VERSION 5.8 ;
BUSBITCHARS "[]" ;
DIVIDERCHAR "/" ;
UNITS
    DATABASE MICRONS 1000 ;
END UNITS

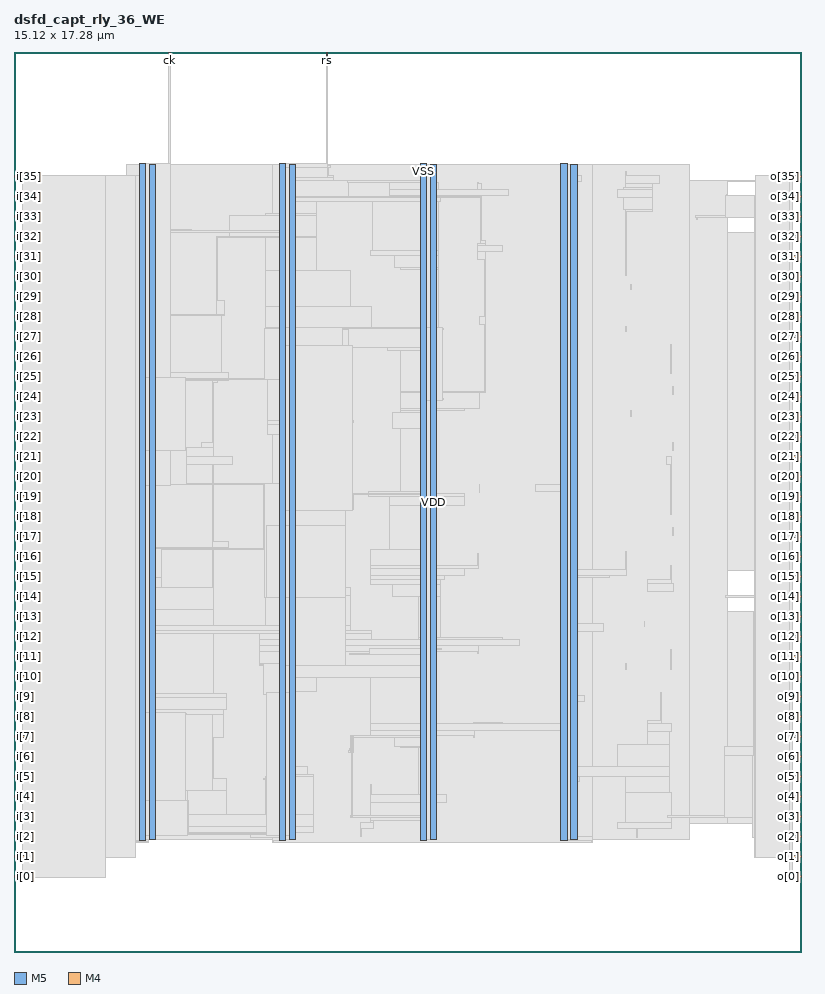
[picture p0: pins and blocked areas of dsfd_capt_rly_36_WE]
MACRO dsfd_capt_rly_36_WE
  FOREIGN dsfd_capt_rly_36_WE 0 0 ;
  CLASS BLOCK ;
  SIZE 15.12 BY 17.28 ;
  PIN ck
    DIRECTION INPUT ;
    USE SIGNAL ;
    PORT
      LAYER M5 ;
        RECT  2.976 17.088 3 17.28 ;
    END
  END ck
  PIN i[0]
    DIRECTION INPUT ;
    USE SIGNAL ;
    PORT
      LAYER M4 ;
        RECT  0 1.44 0.192 1.464 ;
    END
  END i[0]
  PIN i[10]
    DIRECTION INPUT ;
    USE SIGNAL ;
    PORT
      LAYER M4 ;
        RECT  0 5.28 0.192 5.304 ;
    END
  END i[10]
  PIN i[11]
    DIRECTION INPUT ;
    USE SIGNAL ;
    PORT
      LAYER M4 ;
        RECT  0 5.664 0.192 5.688 ;
    END
  END i[11]
  PIN i[12]
    DIRECTION INPUT ;
    USE SIGNAL ;
    PORT
      LAYER M4 ;
        RECT  0 6.048 0.192 6.072 ;
    END
  END i[12]
  PIN i[13]
    DIRECTION INPUT ;
    USE SIGNAL ;
    PORT
      LAYER M4 ;
        RECT  0 6.432 0.192 6.456 ;
    END
  END i[13]
  PIN i[14]
    DIRECTION INPUT ;
    USE SIGNAL ;
    PORT
      LAYER M4 ;
        RECT  0 6.816 0.192 6.84 ;
    END
  END i[14]
  PIN i[15]
    DIRECTION INPUT ;
    USE SIGNAL ;
    PORT
      LAYER M4 ;
        RECT  0 7.2 0.192 7.224 ;
    END
  END i[15]
  PIN i[16]
    DIRECTION INPUT ;
    USE SIGNAL ;
    PORT
      LAYER M4 ;
        RECT  0 7.584 0.192 7.608 ;
    END
  END i[16]
  PIN i[17]
    DIRECTION INPUT ;
    USE SIGNAL ;
    PORT
      LAYER M4 ;
        RECT  0 7.968 0.192 7.992 ;
    END
  END i[17]
  PIN i[18]
    DIRECTION INPUT ;
    USE SIGNAL ;
    PORT
      LAYER M4 ;
        RECT  0 8.352 0.192 8.376 ;
    END
  END i[18]
  PIN i[19]
    DIRECTION INPUT ;
    USE SIGNAL ;
    PORT
      LAYER M4 ;
        RECT  0 8.736 0.192 8.76 ;
    END
  END i[19]
  PIN i[1]
    DIRECTION INPUT ;
    USE SIGNAL ;
    PORT
      LAYER M4 ;
        RECT  0 1.824 0.192 1.848 ;
    END
  END i[1]
  PIN i[20]
    DIRECTION INPUT ;
    USE SIGNAL ;
    PORT
      LAYER M4 ;
        RECT  0 9.12 0.192 9.144 ;
    END
  END i[20]
  PIN i[21]
    DIRECTION INPUT ;
    USE SIGNAL ;
    PORT
      LAYER M4 ;
        RECT  0 9.504 0.192 9.528 ;
    END
  END i[21]
  PIN i[22]
    DIRECTION INPUT ;
    USE SIGNAL ;
    PORT
      LAYER M4 ;
        RECT  0 9.888 0.192 9.912 ;
    END
  END i[22]
  PIN i[23]
    DIRECTION INPUT ;
    USE SIGNAL ;
    PORT
      LAYER M4 ;
        RECT  0 10.272 0.192 10.296 ;
    END
  END i[23]
  PIN i[24]
    DIRECTION INPUT ;
    USE SIGNAL ;
    PORT
      LAYER M4 ;
        RECT  0 10.656 0.192 10.68 ;
    END
  END i[24]
  PIN i[25]
    DIRECTION INPUT ;
    USE SIGNAL ;
    PORT
      LAYER M4 ;
        RECT  0 11.04 0.192 11.064 ;
    END
  END i[25]
  PIN i[26]
    DIRECTION INPUT ;
    USE SIGNAL ;
    PORT
      LAYER M4 ;
        RECT  0 11.424 0.192 11.448 ;
    END
  END i[26]
  PIN i[27]
    DIRECTION INPUT ;
    USE SIGNAL ;
    PORT
      LAYER M4 ;
        RECT  0 11.808 0.192 11.832 ;
    END
  END i[27]
  PIN i[28]
    DIRECTION INPUT ;
    USE SIGNAL ;
    PORT
      LAYER M4 ;
        RECT  0 12.192 0.192 12.216 ;
    END
  END i[28]
  PIN i[29]
    DIRECTION INPUT ;
    USE SIGNAL ;
    PORT
      LAYER M4 ;
        RECT  0 12.576 0.192 12.6 ;
    END
  END i[29]
  PIN i[2]
    DIRECTION INPUT ;
    USE SIGNAL ;
    PORT
      LAYER M4 ;
        RECT  0 2.208 0.192 2.232 ;
    END
  END i[2]
  PIN i[30]
    DIRECTION INPUT ;
    USE SIGNAL ;
    PORT
      LAYER M4 ;
        RECT  0 12.96 0.192 12.984 ;
    END
  END i[30]
  PIN i[31]
    DIRECTION INPUT ;
    USE SIGNAL ;
    PORT
      LAYER M4 ;
        RECT  0 13.344 0.192 13.368 ;
    END
  END i[31]
  PIN i[32]
    DIRECTION INPUT ;
    USE SIGNAL ;
    PORT
      LAYER M4 ;
        RECT  0 13.728 0.192 13.752 ;
    END
  END i[32]
  PIN i[33]
    DIRECTION INPUT ;
    USE SIGNAL ;
    PORT
      LAYER M4 ;
        RECT  0 14.112 0.192 14.136 ;
    END
  END i[33]
  PIN i[34]
    DIRECTION INPUT ;
    USE SIGNAL ;
    PORT
      LAYER M4 ;
        RECT  0 14.496 0.192 14.52 ;
    END
  END i[34]
  PIN i[35]
    DIRECTION INPUT ;
    USE SIGNAL ;
    PORT
      LAYER M4 ;
        RECT  0 14.88 0.192 14.904 ;
    END
  END i[35]
  PIN i[3]
    DIRECTION INPUT ;
    USE SIGNAL ;
    PORT
      LAYER M4 ;
        RECT  0 2.592 0.192 2.616 ;
    END
  END i[3]
  PIN i[4]
    DIRECTION INPUT ;
    USE SIGNAL ;
    PORT
      LAYER M4 ;
        RECT  0 2.976 0.192 3 ;
    END
  END i[4]
  PIN i[5]
    DIRECTION INPUT ;
    USE SIGNAL ;
    PORT
      LAYER M4 ;
        RECT  0 3.36 0.192 3.384 ;
    END
  END i[5]
  PIN i[6]
    DIRECTION INPUT ;
    USE SIGNAL ;
    PORT
      LAYER M4 ;
        RECT  0 3.744 0.192 3.768 ;
    END
  END i[6]
  PIN i[7]
    DIRECTION INPUT ;
    USE SIGNAL ;
    PORT
      LAYER M4 ;
        RECT  0 4.128 0.192 4.152 ;
    END
  END i[7]
  PIN i[8]
    DIRECTION INPUT ;
    USE SIGNAL ;
    PORT
      LAYER M4 ;
        RECT  0 4.512 0.192 4.536 ;
    END
  END i[8]
  PIN i[9]
    DIRECTION INPUT ;
    USE SIGNAL ;
    PORT
      LAYER M4 ;
        RECT  0 4.896 0.192 4.92 ;
    END
  END i[9]
  PIN o[0]
    DIRECTION OUTPUT ;
    USE SIGNAL ;
    PORT
      LAYER M4 ;
        RECT  14.928 1.44 15.12 1.464 ;
    END
  END o[0]
  PIN o[10]
    DIRECTION OUTPUT ;
    USE SIGNAL ;
    PORT
      LAYER M4 ;
        RECT  14.928 5.28 15.12 5.304 ;
    END
  END o[10]
  PIN o[11]
    DIRECTION OUTPUT ;
    USE SIGNAL ;
    PORT
      LAYER M4 ;
        RECT  14.928 5.664 15.12 5.688 ;
    END
  END o[11]
  PIN o[12]
    DIRECTION OUTPUT ;
    USE SIGNAL ;
    PORT
      LAYER M4 ;
        RECT  14.928 6.048 15.12 6.072 ;
    END
  END o[12]
  PIN o[13]
    DIRECTION OUTPUT ;
    USE SIGNAL ;
    PORT
      LAYER M4 ;
        RECT  14.928 6.432 15.12 6.456 ;
    END
  END o[13]
  PIN o[14]
    DIRECTION OUTPUT ;
    USE SIGNAL ;
    PORT
      LAYER M4 ;
        RECT  14.928 6.816 15.12 6.84 ;
    END
  END o[14]
  PIN o[15]
    DIRECTION OUTPUT ;
    USE SIGNAL ;
    PORT
      LAYER M4 ;
        RECT  14.928 7.2 15.12 7.224 ;
    END
  END o[15]
  PIN o[16]
    DIRECTION OUTPUT ;
    USE SIGNAL ;
    PORT
      LAYER M4 ;
        RECT  14.928 7.584 15.12 7.608 ;
    END
  END o[16]
  PIN o[17]
    DIRECTION OUTPUT ;
    USE SIGNAL ;
    PORT
      LAYER M4 ;
        RECT  14.928 7.968 15.12 7.992 ;
    END
  END o[17]
  PIN o[18]
    DIRECTION OUTPUT ;
    USE SIGNAL ;
    PORT
      LAYER M4 ;
        RECT  14.928 8.352 15.12 8.376 ;
    END
  END o[18]
  PIN o[19]
    DIRECTION OUTPUT ;
    USE SIGNAL ;
    PORT
      LAYER M4 ;
        RECT  14.928 8.736 15.12 8.76 ;
    END
  END o[19]
  PIN o[1]
    DIRECTION OUTPUT ;
    USE SIGNAL ;
    PORT
      LAYER M4 ;
        RECT  14.928 1.824 15.12 1.848 ;
    END
  END o[1]
  PIN o[20]
    DIRECTION OUTPUT ;
    USE SIGNAL ;
    PORT
      LAYER M4 ;
        RECT  14.928 9.12 15.12 9.144 ;
    END
  END o[20]
  PIN o[21]
    DIRECTION OUTPUT ;
    USE SIGNAL ;
    PORT
      LAYER M4 ;
        RECT  14.928 9.504 15.12 9.528 ;
    END
  END o[21]
  PIN o[22]
    DIRECTION OUTPUT ;
    USE SIGNAL ;
    PORT
      LAYER M4 ;
        RECT  14.928 9.888 15.12 9.912 ;
    END
  END o[22]
  PIN o[23]
    DIRECTION OUTPUT ;
    USE SIGNAL ;
    PORT
      LAYER M4 ;
        RECT  14.928 10.272 15.12 10.296 ;
    END
  END o[23]
  PIN o[24]
    DIRECTION OUTPUT ;
    USE SIGNAL ;
    PORT
      LAYER M4 ;
        RECT  14.928 10.656 15.12 10.68 ;
    END
  END o[24]
  PIN o[25]
    DIRECTION OUTPUT ;
    USE SIGNAL ;
    PORT
      LAYER M4 ;
        RECT  14.928 11.04 15.12 11.064 ;
    END
  END o[25]
  PIN o[26]
    DIRECTION OUTPUT ;
    USE SIGNAL ;
    PORT
      LAYER M4 ;
        RECT  14.928 11.424 15.12 11.448 ;
    END
  END o[26]
  PIN o[27]
    DIRECTION OUTPUT ;
    USE SIGNAL ;
    PORT
      LAYER M4 ;
        RECT  14.928 11.808 15.12 11.832 ;
    END
  END o[27]
  PIN o[28]
    DIRECTION OUTPUT ;
    USE SIGNAL ;
    PORT
      LAYER M4 ;
        RECT  14.928 12.192 15.12 12.216 ;
    END
  END o[28]
  PIN o[29]
    DIRECTION OUTPUT ;
    USE SIGNAL ;
    PORT
      LAYER M4 ;
        RECT  14.928 12.576 15.12 12.6 ;
    END
  END o[29]
  PIN o[2]
    DIRECTION OUTPUT ;
    USE SIGNAL ;
    PORT
      LAYER M4 ;
        RECT  14.928 2.208 15.12 2.232 ;
    END
  END o[2]
  PIN o[30]
    DIRECTION OUTPUT ;
    USE SIGNAL ;
    PORT
      LAYER M4 ;
        RECT  14.928 12.96 15.12 12.984 ;
    END
  END o[30]
  PIN o[31]
    DIRECTION OUTPUT ;
    USE SIGNAL ;
    PORT
      LAYER M4 ;
        RECT  14.928 13.344 15.12 13.368 ;
    END
  END o[31]
  PIN o[32]
    DIRECTION OUTPUT ;
    USE SIGNAL ;
    PORT
      LAYER M4 ;
        RECT  14.928 13.728 15.12 13.752 ;
    END
  END o[32]
  PIN o[33]
    DIRECTION OUTPUT ;
    USE SIGNAL ;
    PORT
      LAYER M4 ;
        RECT  14.928 14.112 15.12 14.136 ;
    END
  END o[33]
  PIN o[34]
    DIRECTION OUTPUT ;
    USE SIGNAL ;
    PORT
      LAYER M4 ;
        RECT  14.928 14.496 15.12 14.52 ;
    END
  END o[34]
  PIN o[35]
    DIRECTION OUTPUT ;
    USE SIGNAL ;
    PORT
      LAYER M4 ;
        RECT  14.928 14.88 15.12 14.904 ;
    END
  END o[35]
  PIN o[3]
    DIRECTION OUTPUT ;
    USE SIGNAL ;
    PORT
      LAYER M4 ;
        RECT  14.928 2.592 15.12 2.616 ;
    END
  END o[3]
  PIN o[4]
    DIRECTION OUTPUT ;
    USE SIGNAL ;
    PORT
      LAYER M4 ;
        RECT  14.928 2.976 15.12 3 ;
    END
  END o[4]
  PIN o[5]
    DIRECTION OUTPUT ;
    USE SIGNAL ;
    PORT
      LAYER M4 ;
        RECT  14.928 3.36 15.12 3.384 ;
    END
  END o[5]
  PIN o[6]
    DIRECTION OUTPUT ;
    USE SIGNAL ;
    PORT
      LAYER M4 ;
        RECT  14.928 3.744 15.12 3.768 ;
    END
  END o[6]
  PIN o[7]
    DIRECTION OUTPUT ;
    USE SIGNAL ;
    PORT
      LAYER M4 ;
        RECT  14.928 4.128 15.12 4.152 ;
    END
  END o[7]
  PIN o[8]
    DIRECTION OUTPUT ;
    USE SIGNAL ;
    PORT
      LAYER M4 ;
        RECT  14.928 4.512 15.12 4.536 ;
    END
  END o[8]
  PIN o[9]
    DIRECTION OUTPUT ;
    USE SIGNAL ;
    PORT
      LAYER M4 ;
        RECT  14.928 4.896 15.12 4.92 ;
    END
  END o[9]
  PIN rs
    DIRECTION INPUT ;
    USE SIGNAL ;
    PORT
      LAYER M5 ;
        RECT  6 17.088 6.024 17.28 ;
    END
  END rs
  PIN VDD
    DIRECTION INOUT ;
    USE POWER ;
    PORT
      LAYER M5 ;
        RECT  10.692 2.151 10.812 15.129 ;
        RECT  7.992 2.151 8.112 15.129 ;
        RECT  5.292 2.151 5.412 15.129 ;
        RECT  2.592 2.151 2.712 15.129 ;
    END
  END VDD
  PIN VSS
    DIRECTION INOUT ;
    USE GROUND ;
    PORT
      LAYER M5 ;
        RECT  10.5 2.137 10.62 15.143 ;
        RECT  7.8 2.137 7.92 15.143 ;
        RECT  5.1 2.137 5.22 15.143 ;
        RECT  2.4 2.137 2.52 15.143 ;
    END
  END VSS
  OBS
    LAYER RVTN ;
     RECT  2.16 2.16 12.96 2.295 ;
     RECT  2.16 2.565 12.96 2.835 ;
     RECT  2.16 3.105 12.96 3.375 ;
     RECT  2.16 3.645 12.96 3.915 ;
     RECT  2.16 4.185 12.96 4.455 ;
     RECT  2.16 4.725 12.96 4.995 ;
     RECT  2.16 5.265 12.96 5.535 ;
     RECT  2.16 5.805 12.96 6.075 ;
     RECT  2.16 6.345 12.96 6.615 ;
     RECT  2.16 6.885 12.96 7.155 ;
     RECT  2.16 7.425 12.96 7.695 ;
     RECT  2.16 7.965 12.96 8.235 ;
     RECT  2.16 8.505 12.96 8.775 ;
     RECT  2.16 9.045 12.96 9.315 ;
     RECT  2.16 9.585 12.96 9.855 ;
     RECT  2.16 10.125 12.96 10.395 ;
     RECT  2.16 10.665 12.96 10.935 ;
     RECT  2.16 11.205 12.96 11.475 ;
     RECT  2.16 11.745 12.96 12.015 ;
     RECT  2.16 12.285 12.96 12.555 ;
     RECT  2.16 12.825 12.96 13.095 ;
     RECT  2.16 13.365 12.96 13.635 ;
     RECT  2.16 13.905 12.96 14.175 ;
     RECT  2.16 14.445 12.96 14.715 ;
     RECT  2.16 14.985 12.96 15.12 ;
    LAYER RVTP ;
     RECT  2.16 2.295 12.96 2.565 ;
     RECT  2.16 2.835 12.96 3.105 ;
     RECT  2.16 3.375 12.96 3.645 ;
     RECT  2.16 3.915 12.96 4.185 ;
     RECT  2.16 4.455 12.96 4.725 ;
     RECT  2.16 4.995 12.96 5.265 ;
     RECT  2.16 5.535 12.96 5.805 ;
     RECT  2.16 6.075 12.96 6.345 ;
     RECT  2.16 6.615 12.96 6.885 ;
     RECT  2.16 7.155 12.96 7.425 ;
     RECT  2.16 7.695 12.96 7.965 ;
     RECT  2.16 8.235 12.96 8.505 ;
     RECT  2.16 8.775 12.96 9.045 ;
     RECT  2.16 9.315 12.96 9.585 ;
     RECT  2.16 9.855 12.96 10.125 ;
     RECT  2.16 10.395 12.96 10.665 ;
     RECT  2.16 10.935 12.96 11.205 ;
     RECT  2.16 11.475 12.96 11.745 ;
     RECT  2.16 12.015 12.96 12.285 ;
     RECT  2.16 12.555 12.96 12.825 ;
     RECT  2.16 13.095 12.96 13.365 ;
     RECT  2.16 13.635 12.96 13.905 ;
     RECT  2.16 14.175 12.96 14.445 ;
     RECT  2.16 14.715 12.96 14.985 ;
    LAYER M1 ;
     RECT  2.16 2.151 12.96 15.129 ;
    LAYER M2 ;
     RECT  1.723 2.106 2.16 2.124 ;
     RECT  2.16 2.106 2.579 15.129 ;
     RECT  2.579 2.151 4.963 15.129 ;
     RECT  4.963 2.106 11.111 15.129 ;
     RECT  11.111 2.151 12.96 15.129 ;
     RECT  12.96 2.466 13.703 14.814 ;
     RECT  13.703 2.466 14.207 6.534 ;
     RECT  14.207 3.006 14.243 3.294 ;
     RECT  14.207 4.122 14.243 6.534 ;
     RECT  13.703 7.326 14.243 13.824 ;
     RECT  13.703 14.796 14.279 14.814 ;
     RECT  14.243 3.006 14.927 3.024 ;
     RECT  14.243 7.938 14.927 7.956 ;
     RECT  14.243 11.376 14.927 11.394 ;
    LAYER M3 ;
     RECT  1.728 1.435 1.746 1.819 ;
     RECT  14.904 1.435 14.922 1.819 ;
     RECT  1.728 1.819 2.322 2.101 ;
     RECT  1.728 2.101 2.574 2.129 ;
     RECT  4.968 2.101 4.986 2.143 ;
     RECT  11.088 2.101 11.106 2.143 ;
     RECT  4.968 2.143 5.205 2.191 ;
     RECT  14.22 1.819 14.922 2.203 ;
     RECT  10.515 2.143 11.106 2.219 ;
     RECT  2.268 2.129 2.574 2.255 ;
     RECT  3.312 2.251 3.33 2.299 ;
     RECT  4.536 2.191 5.205 2.299 ;
     RECT  6.66 2.227 6.678 2.371 ;
     RECT  11.952 2.191 11.97 2.371 ;
     RECT  2.304 2.255 2.574 2.413 ;
     RECT  3.312 2.299 5.742 2.413 ;
     RECT  7.815 2.143 7.905 2.413 ;
     RECT  6.66 2.371 6.894 2.489 ;
     RECT  11.592 2.371 12.618 2.489 ;
     RECT  6.84 2.489 6.894 2.533 ;
     RECT  7.815 2.413 8.097 2.533 ;
     RECT  2.304 2.413 5.742 2.633 ;
     RECT  6.84 2.533 8.097 2.875 ;
     RECT  6.84 2.875 8.298 3.029 ;
     RECT  14.184 2.203 14.922 3.029 ;
     RECT  11.736 2.489 12.618 3.065 ;
     RECT  2.304 2.633 4.086 3.101 ;
     RECT  6.84 3.029 6.858 3.209 ;
     RECT  10.515 2.219 10.797 3.271 ;
     RECT  14.184 3.029 14.238 3.299 ;
     RECT  3.816 3.101 4.086 3.335 ;
     RECT  14.184 3.299 14.202 3.355 ;
     RECT  4.824 2.633 5.742 3.371 ;
     RECT  10.515 3.271 10.854 3.379 ;
     RECT  11.736 3.065 12.582 3.379 ;
     RECT  2.304 3.101 2.826 3.389 ;
     RECT  5.115 3.371 5.742 3.407 ;
     RECT  5.115 3.407 5.634 3.569 ;
     RECT  10.515 3.379 12.582 3.569 ;
     RECT  2.304 3.389 2.697 3.875 ;
     RECT  6.444 3.835 6.462 3.911 ;
     RECT  7.776 3.029 8.097 3.919 ;
     RECT  13.644 3.355 14.202 3.947 ;
     RECT  7.416 3.919 8.097 3.955 ;
     RECT  11.592 3.569 12.582 3.983 ;
     RECT  2.415 3.875 2.697 4.117 ;
     RECT  3.816 3.335 3.834 4.117 ;
     RECT  7.308 3.955 8.097 4.117 ;
     RECT  6.84 4.117 8.097 4.153 ;
     RECT  8.82 4.117 8.838 4.153 ;
     RECT  12.168 3.983 12.582 4.225 ;
     RECT  6.84 4.153 8.838 4.261 ;
     RECT  10.515 3.569 10.797 4.261 ;
     RECT  6.84 4.261 10.797 4.379 ;
     RECT  12.168 4.225 12.618 4.379 ;
     RECT  8.82 4.379 9.378 4.415 ;
     RECT  12.168 4.379 12.438 4.451 ;
     RECT  2.415 4.117 2.754 4.555 ;
     RECT  3.816 4.117 4.014 4.555 ;
     RECT  2.415 4.555 4.014 4.657 ;
     RECT  10.515 4.379 10.797 4.801 ;
     RECT  2.415 4.657 4.086 4.891 ;
     RECT  10.515 4.801 10.962 4.919 ;
     RECT  5.115 3.569 5.397 4.939 ;
     RECT  2.304 4.891 4.086 4.955 ;
     RECT  12.42 4.451 12.438 4.991 ;
     RECT  4.824 4.939 5.397 4.999 ;
     RECT  4.824 4.999 5.814 5.269 ;
     RECT  6.84 4.379 8.097 5.269 ;
     RECT  4.824 5.269 8.097 5.503 ;
     RECT  11.736 5.431 11.754 5.531 ;
     RECT  4.716 5.503 8.097 5.773 ;
     RECT  8.892 5.737 8.91 5.773 ;
     RECT  12.6 5.431 12.618 5.801 ;
     RECT  4.716 5.773 8.91 5.881 ;
     RECT  4.716 5.881 9.702 5.999 ;
     RECT  7.776 5.999 9.378 6.035 ;
     RECT  2.304 4.955 3.834 6.115 ;
     RECT  4.716 5.999 6.858 6.115 ;
     RECT  10.515 4.919 10.797 6.151 ;
     RECT  2.304 6.115 6.858 6.179 ;
     RECT  2.304 6.179 6.462 6.269 ;
     RECT  10.515 6.151 11.322 6.305 ;
     RECT  12.096 6.241 12.114 6.341 ;
     RECT  2.304 6.269 3.834 6.575 ;
     RECT  14.22 4.117 14.238 6.808 ;
     RECT  7.776 6.035 8.19 6.817 ;
     RECT  4.824 6.269 6.462 6.845 ;
     RECT  13.68 6.808 14.238 6.845 ;
     RECT  2.415 6.575 3.834 6.989 ;
     RECT  5.115 6.845 6.462 6.989 ;
     RECT  7.272 6.817 8.19 7.051 ;
     RECT  12.168 6.925 12.654 7.079 ;
     RECT  12.168 7.079 12.618 7.151 ;
     RECT  6.84 7.051 8.19 7.159 ;
     RECT  10.515 6.305 10.797 7.195 ;
     RECT  6.84 7.159 8.262 7.231 ;
     RECT  10.515 7.195 11.43 7.231 ;
     RECT  10.515 7.231 11.754 7.349 ;
     RECT  6.84 7.231 8.658 7.357 ;
     RECT  6.84 7.357 8.91 7.421 ;
     RECT  12.6 7.151 12.618 7.421 ;
     RECT  2.415 6.989 2.826 7.579 ;
     RECT  14.22 6.845 14.238 7.619 ;
     RECT  8.892 7.421 8.91 7.655 ;
     RECT  11.736 7.349 11.754 7.691 ;
     RECT  2.304 7.579 2.826 7.723 ;
     RECT  3.816 6.989 3.834 7.723 ;
     RECT  6.84 7.421 8.097 7.727 ;
     RECT  2.304 7.723 3.834 7.735 ;
     RECT  2.304 7.735 4.122 7.763 ;
     RECT  3.816 7.763 4.122 7.889 ;
     RECT  14.904 7.933 14.922 7.997 ;
     RECT  5.115 6.989 5.814 8.155 ;
     RECT  12.636 8.005 12.654 8.159 ;
     RECT  2.304 7.763 2.697 8.195 ;
     RECT  4.824 8.155 5.814 8.231 ;
     RECT  5.115 8.231 5.814 8.491 ;
     RECT  5.115 8.491 6.462 8.537 ;
     RECT  7.2 7.727 8.097 8.581 ;
     RECT  7.2 8.581 8.658 8.743 ;
     RECT  6.804 8.743 8.658 8.807 ;
     RECT  6.804 8.807 8.097 8.843 ;
     RECT  10.515 7.349 10.797 8.851 ;
     RECT  8.928 8.815 8.946 8.969 ;
     RECT  10.008 8.851 10.797 8.969 ;
     RECT  2.415 8.195 2.697 9.115 ;
     RECT  2.304 9.115 2.697 9.355 ;
     RECT  3.816 7.889 3.834 9.355 ;
     RECT  12.6 8.401 12.618 9.355 ;
     RECT  5.115 8.537 6.03 9.391 ;
     RECT  2.304 9.355 4.194 9.509 ;
     RECT  12.528 9.355 12.618 9.509 ;
     RECT  2.304 9.509 3.834 9.677 ;
     RECT  3.6 9.677 3.834 9.779 ;
     RECT  12.636 9.625 12.654 9.779 ;
     RECT  5.115 9.391 6.246 9.931 ;
     RECT  7.416 8.843 8.097 10.057 ;
     RECT  4.86 9.931 6.246 10.129 ;
     RECT  4.86 10.129 6.462 10.205 ;
     RECT  7.272 10.057 8.097 10.355 ;
     RECT  11.844 10.291 11.862 10.391 ;
     RECT  7.416 10.355 8.097 10.399 ;
     RECT  7.416 10.399 8.658 10.435 ;
     RECT  2.304 9.677 2.697 10.741 ;
     RECT  7.416 10.435 8.946 10.741 ;
     RECT  7.416 10.741 9.054 10.769 ;
     RECT  12.636 10.705 12.654 10.859 ;
     RECT  3.816 9.779 3.834 10.939 ;
     RECT  2.304 10.741 2.79 10.975 ;
     RECT  3.816 10.939 3.906 10.975 ;
     RECT  2.304 10.975 4.122 11.129 ;
     RECT  4.86 10.205 5.814 11.209 ;
     RECT  14.22 8.347 14.238 11.371 ;
     RECT  14.22 11.371 14.922 11.453 ;
     RECT  7.416 10.769 8.097 11.551 ;
     RECT  4.824 11.209 5.814 11.611 ;
     RECT  7.164 11.551 8.097 11.611 ;
     RECT  12.6 11.101 12.618 11.669 ;
     RECT  4.824 11.611 8.097 11.947 ;
     RECT  4.824 11.947 8.154 11.981 ;
     RECT  11.736 11.911 11.754 12.011 ;
     RECT  9.036 10.769 9.054 12.055 ;
     RECT  8.928 12.055 9.054 12.209 ;
     RECT  2.304 11.129 3.978 12.217 ;
     RECT  2.304 12.217 4.05 12.245 ;
     RECT  4.824 11.981 6.858 12.389 ;
     RECT  3.888 12.245 4.05 12.515 ;
     RECT  11.844 12.721 11.862 12.821 ;
     RECT  4.824 12.389 6.462 13.091 ;
     RECT  7.815 11.981 8.154 13.099 ;
     RECT  7.416 13.099 8.154 13.135 ;
     RECT  9.036 12.209 9.054 13.297 ;
     RECT  7.308 13.135 8.154 13.369 ;
     RECT  2.304 12.245 2.697 13.373 ;
     RECT  8.892 13.297 9.054 13.441 ;
     RECT  6.84 13.369 8.154 13.469 ;
     RECT  8.892 13.441 9.378 13.559 ;
     RECT  8.892 13.559 9.054 13.595 ;
     RECT  8.964 13.595 9.054 13.667 ;
     RECT  3.888 12.515 3.906 13.711 ;
     RECT  4.824 13.091 5.814 13.711 ;
     RECT  3.888 13.711 5.814 13.739 ;
     RECT  2.412 13.373 2.697 13.819 ;
     RECT  14.22 11.453 14.238 13.829 ;
     RECT  2.412 13.819 3.402 13.865 ;
     RECT  4.14 13.739 5.814 14.135 ;
     RECT  13.104 14.071 13.122 14.141 ;
     RECT  4.824 14.135 5.814 14.171 ;
     RECT  11.736 12.991 11.754 14.215 ;
     RECT  11.736 14.215 12.258 14.251 ;
     RECT  5.115 14.171 5.814 14.413 ;
     RECT  6.876 13.469 8.154 14.413 ;
     RECT  5.115 14.413 8.19 14.485 ;
     RECT  8.964 13.667 8.982 14.485 ;
     RECT  11.7 14.251 12.258 14.485 ;
     RECT  2.412 13.865 2.697 14.491 ;
     RECT  5.115 14.485 8.982 14.513 ;
     RECT  7.2 14.513 8.982 14.521 ;
     RECT  13.68 14.491 13.698 14.549 ;
     RECT  7.2 14.521 9.486 14.639 ;
     RECT  11.592 14.485 12.258 14.639 ;
     RECT  11.7 14.639 12.258 14.675 ;
     RECT  8.892 14.639 8.982 14.747 ;
     RECT  11.736 14.675 12.258 14.755 ;
     RECT  7.2 14.639 8.154 14.783 ;
     RECT  8.892 14.747 8.91 14.783 ;
     RECT  10.515 8.969 10.797 14.791 ;
     RECT  5.115 14.513 6.426 14.813 ;
     RECT  2.304 14.491 2.697 14.867 ;
     RECT  5.115 14.813 6.138 14.867 ;
     RECT  7.815 14.783 8.097 14.867 ;
     RECT  2.304 14.867 2.505 14.909 ;
     RECT  6.012 14.867 6.138 14.909 ;
     RECT  10.515 14.791 10.89 14.909 ;
     RECT  11.736 14.755 12.402 14.909 ;
     RECT  14.256 14.791 14.274 14.909 ;
     RECT  11.736 14.909 11.754 14.981 ;
     RECT  6.012 14.909 6.03 15.101 ;
     RECT  2.415 14.909 2.505 15.137 ;
     RECT  5.115 14.867 5.205 15.137 ;
     RECT  7.815 14.867 7.905 15.137 ;
     RECT  10.515 14.909 10.605 15.137 ;
    LAYER M4 ;
     RECT  0.156 1.44 1.757 14.904 ;
     RECT  1.757 1.824 2.333 14.904 ;
     RECT  2.333 2.148 2.408 14.904 ;
     RECT  2.408 2.148 2.512 15.132 ;
     RECT  2.512 2.256 2.704 14.862 ;
     RECT  2.704 2.256 2.765 4.584 ;
     RECT  2.704 10.992 2.765 11.448 ;
     RECT  2.765 2.256 2.837 3.384 ;
     RECT  2.704 7.2 2.837 7.752 ;
     RECT  2.765 4.56 3.305 4.584 ;
     RECT  2.704 8.976 3.305 9.672 ;
     RECT  2.837 2.256 3.34 3.096 ;
     RECT  3.34 2.256 3.349 2.904 ;
     RECT  4.705 5.52 4.796 5.544 ;
     RECT  2.837 7.728 4.796 7.752 ;
     RECT  3.305 8.976 4.796 9 ;
     RECT  4.796 7.728 4.813 9 ;
     RECT  2.765 10.992 4.813 11.016 ;
     RECT  3.349 2.256 5.108 2.28 ;
     RECT  4.796 3.312 5.108 3.336 ;
     RECT  4.796 4.944 5.108 5.544 ;
     RECT  4.813 6.816 5.108 9 ;
     RECT  4.813 10.992 5.108 11.976 ;
     RECT  2.704 13.824 5.108 13.848 ;
     RECT  5.108 2.148 5.212 15.132 ;
     RECT  5.212 2.418 5.404 15.096 ;
     RECT  5.404 8.784 5.717 9 ;
     RECT  5.404 15.072 6.076 15.096 ;
     RECT  5.717 8.784 6.323 8.904 ;
     RECT  5.404 5.52 6.371 5.544 ;
     RECT  6.323 8.784 6.428 8.808 ;
     RECT  5.404 11.952 6.431 11.976 ;
     RECT  6.428 3.84 6.469 3.864 ;
     RECT  6.469 3.84 6.515 4.152 ;
     RECT  6.428 8.496 6.515 8.808 ;
     RECT  6.428 10.176 6.515 10.2 ;
     RECT  6.433 5.712 6.829 5.736 ;
     RECT  6.469 2.592 7.808 2.616 ;
     RECT  6.515 4.128 7.808 4.152 ;
     RECT  6.829 5.712 7.808 5.832 ;
     RECT  6.515 8.784 7.808 8.808 ;
     RECT  6.431 11.616 7.808 11.976 ;
     RECT  6.397 14.784 7.808 14.808 ;
     RECT  7.808 2.148 7.912 15.132 ;
     RECT  7.912 2.418 8.104 14.862 ;
     RECT  8.104 5.808 8.201 5.832 ;
     RECT  8.104 10.608 8.243 10.632 ;
     RECT  8.104 11.952 8.243 11.976 ;
     RECT  10.508 2.148 10.612 15.132 ;
     RECT  10.612 2.418 10.804 14.862 ;
     RECT  12.553 2.592 13.633 2.616 ;
     RECT  13.093 14.112 13.669 14.136 ;
     RECT  13.633 2.592 14.173 3.768 ;
     RECT  14.173 2.208 14.209 3.768 ;
     RECT  13.669 6.816 14.209 6.84 ;
     RECT  13.669 14.112 14.209 14.52 ;
     RECT  14.209 1.824 14.245 14.52 ;
     RECT  14.245 1.824 14.893 14.904 ;
     RECT  14.893 1.44 14.94 14.904 ;
    LAYER M5 ;
     RECT  2.4 2.137 2.52 2.151 ;
     RECT  5.1 2.137 5.22 2.151 ;
     RECT  7.8 2.137 7.92 2.151 ;
     RECT  10.5 2.137 10.62 2.151 ;
     RECT  2.4 2.151 2.712 2.245 ;
     RECT  5.1 2.151 5.412 2.245 ;
     RECT  2.4 2.245 3.336 2.915 ;
     RECT  6.48 2.581 6.504 4.163 ;
     RECT  2.4 2.915 3.288 4.595 ;
     RECT  4.848 2.245 5.412 4.979 ;
     RECT  5.1 4.979 5.412 5.509 ;
     RECT  5.1 5.509 6.36 6.805 ;
     RECT  4.848 6.805 6.36 8.195 ;
     RECT  5.1 8.195 6.36 8.485 ;
     RECT  2.4 4.595 2.712 8.965 ;
     RECT  2.4 8.965 3 9.637 ;
     RECT  7.8 2.151 8.112 10.597 ;
     RECT  2.4 9.637 3.288 11.027 ;
     RECT  5.1 8.485 6.504 11.651 ;
     RECT  5.1 11.651 6.312 11.987 ;
     RECT  7.8 10.597 8.232 11.987 ;
     RECT  5.1 11.987 5.412 15.061 ;
     RECT  7.8 11.987 8.112 15.129 ;
     RECT  10.5 2.151 10.812 15.129 ;
     RECT  2.4 11.027 3 15.143 ;
     RECT  5.1 15.061 6.024 15.143 ;
     RECT  7.8 15.129 7.92 15.143 ;
     RECT  10.5 15.129 10.62 15.143 ;
     RECT  2.976 15.143 3 17.104 ;
     RECT  6 15.143 6.024 17.104 ;
  END
END dsfd_capt_rly_36_WE
END LIBRARY
